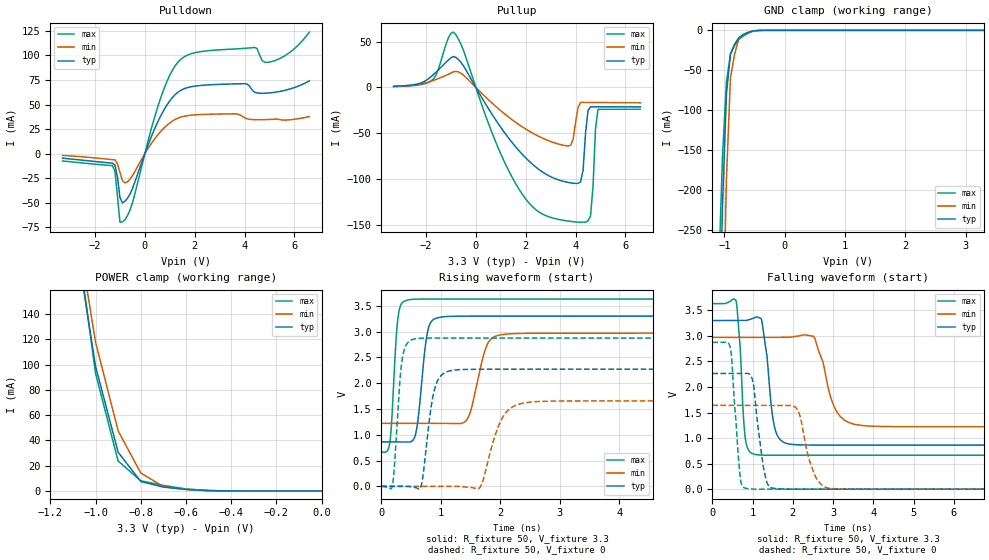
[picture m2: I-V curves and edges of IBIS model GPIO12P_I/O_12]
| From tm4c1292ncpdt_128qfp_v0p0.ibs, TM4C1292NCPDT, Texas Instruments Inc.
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|   Model Cell GPIO12P_I/O_12
[Model]   GPIO12P_I/O_12
Model_type   I/O
Polarity   Non-Inverting
Enable   Active-Low
Vinl =  0.8
Vinh =  2
Cref =  15.0000pF
Rref =  100.0000M
Vref =  0V
Vmeas =  1.65
C_comp   6.029616p   5.226915p   6.778838p
[Model Spec]
Vinl   0.8   0.8   0.8
Vinh   2   2   2
[Temperature Range]   25   125   -40
[Voltage Range]   3.3   2.97   3.63
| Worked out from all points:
|   slope of the pulldown table from 0 to 0.495 V, typ, clamps not added: 15.9 ohm
|   slope of the pullup table from 0 to 0.495 V, typ, clamps not added: 21.8 ohm
|   GND clamp passes 1 mA (typ) near -0.53 V on its own axis
|   POWER clamp passes 1 mA (typ) near -0.58 V on its own axis
|   rising waveform, R_fixture 50, V_fixture 3.3: 20-80 % time 127ps typ, 210ps min, 85.9ps max; typ from 0.861 V to 3.3 V
|   rising waveform, R_fixture 50, V_fixture 0: 20-80 % time 153ps typ, 270ps min, 102ps max; typ from 0 V to 2.26 V
|   falling waveform, R_fixture 50, V_fixture 3.3: 20-80 % time 195ps typ, 372ps min, 122ps max; typ from 3.3 V to 0.861 V
|   falling waveform, R_fixture 50, V_fixture 0: 20-80 % time 208ps typ, 306ps min, 151ps max; typ from 2.26 V to 0 V
| Nom Voltages:
|   IBIASFET=3.3, VDDC=1.2, VDD=3.3, GND=0
| Min Voltages:
|   IBIASFET=2.97, VDDC=1.08, VDD=2.97, GND=0
| Max Voltages:
|   IBIASFET=3.63, VDDC=1.32, VDD=3.63, GND=0
[POWER_clamp]
|   voltage   I(typ)   I(min)   I(max)
-3.3V     3.668A     4.187A     4.057A
-1.067V   175.6mA    191.7mA    181.3mA
-1.033V   137.2mA    154.7mA    137.2mA
-1V       98.66mA    117.8mA    93.17mA
-900mV    30.66mA    47.6mA     23.68mA
-800mV    7.454mA    14.17mA    8.045mA
-700mV    3.021mA    3.466mA    4.326mA
-600mV    1.166mA    1.15mA     1.613mA
-500mV    219.7uA    295.1uA    245.5uA
0V        69.07pA    1.982nA    9.028pA
[Pulldown]
|   voltage   I(typ)   I(min)   I(max)
-3.3V     -4.531mA   -1.809mA   -7.41mA
-1.3V     -9.628mA   -6.013mA   -12.13mA
-1.2V     -11.53mA   -6.246mA   -17.7mA
-1V       -44.52mA   -18.9mA    -69.71mA
-900mV    -49.91mA   -27.35mA   -69.41mA
-500mV    -35.64mA   -22.45mA   -50.16mA
700mV     41.51mA    24.42mA    61.45mA
1.4V      63.88mA    36.91mA    95.09mA
4V        71.26mA    36.57mA    107.3mA
4.4V      62.7mA     34.65mA    108.2mA
5V        61.9mA     34.87mA    93.27mA
6.6V      74.13mA    37.78mA    123.8mA
[Pullup]
|   voltage   I(typ)   I(min)   I(max)
-3.3V     1.279mA    1.197mA    982.3uA
-1.7V     14.18mA    7.771mA    9.423mA
-900mV    33.79mA    17.11mA    60.55mA
1.8V      -71.23mA   -41.94mA   -114.2mA
3.7V      -103.8mA   -63.94mA   -146mA
4V        -104.9mA   -38.28mA   -147mA
4.3V      -90.74mA   -16.33mA   -147.2mA
4.5V      -25.16mA   -16.35mA   -145.8mA
4.6V      -21.1mA    -16.37mA   -140.6mA
4.8V      -21.09mA   -16.4mA    -44.84mA
4.9V      -21.08mA   -16.42mA   -23.95mA
6.6V      -21.2mA    -16.74mA   -23.82mA
[GND_clamp]
|   voltage   I(typ)   I(min)   I(max)
-3.3V     -18.01A    -17.27A    -18.6A
-1.1V     -459.9mA   -734.3mA   -318.7mA
-1.033V   -223.6mA   -411.6mA   -160.4mA
-966.7mV  -80.12mA   -186.8mA   -64.21mA
-900mV    -29.51mA   -59.8mA    -30.11mA
-833.3mV  -17.66mA   -30.4mA    -19.41mA
-766.7mV  -9.785mA   -12.28mA   -11.96mA
-700mV    -5.884mA   -5.445mA   -7.749mA
-500mV    -484.3uA   -573uA     -552.3uA
-366.7mV  -23.48uA   -48.41uA   -21.82uA
3.3V      69.07pA    6.412uA    7.794pA
[Ramp]
| variable   typ   min   max
dV/dt_f  1.5054176/0.20241459n  1.0791279/0.38581502n  1.8336291/0.12747084n
dV/dt_r  1.3955443/0.15677185n  1.0245114/0.27733281n  1.7538476/0.10287361n
R_load = 50
[Rising Waveform]
R_fixture = 50
V_fixture = 3.3
V_fixture_min = 2.97
V_fixture_max = 3.63
|   time   V(typ)   V(min)   V(max)
0s        861.5mV    1.221V     663.5mV
153.3ps   861.5mV    1.221V     944.6mV
290.5ps   861.5mV    1.221V     3.351V
479.8ps   859.5mV    1.221V     3.62V
605.7ps   1.192V     1.221V     3.629V
789.1ps   3.053V     1.221V     3.63V
1.031ns   3.285V     1.221V     3.63V
1.447ns   3.299V     1.308V     3.63V
2.154ns   3.3V       2.956V     3.63V
20.01ns   3.3V       2.97V      3.63V
[Rising Waveform]
R_fixture = 50
V_fixture = 0
V_fixture_min = 0
V_fixture_max = 0
|   time   V(typ)   V(min)   V(max)
0s        0V         0V         0V
181.3ps   0V         0V         -13.98mV
350.9ps   0V         0V         2.466V
592.4ps   -31.5mV    0V         2.864V
918.8ps   1.974V     0V         2.874V
1.215ns   2.252V     0V         2.874V
1.657ns   2.269V     -24.92mV   2.874V
2.033ns   2.27V      1.326V     2.874V
2.584ns   2.271V     1.641V     2.874V
20.02ns   2.264V     1.646V     2.872V
[Falling Waveform]
R_fixture = 50
V_fixture = 3.3
V_fixture_min = 2.97
V_fixture_max = 3.63
|   time   V(typ)   V(min)   V(max)
0s        3.3V       2.97V      3.63V
587.7ps   3.3V       2.97V      3.691V
815ps     3.3V       2.97V      1.016V
1.069ns   3.365V     2.97V      677.8mV
1.238ns   3.251V     2.97V      666.2mV
1.543ns   1.221V     2.97V      664.1mV
1.916ns   882.4mV    2.972V     664.1mV
2.519ns   862.5mV    2.986V     664.2mV
3.673ns   861.6mV    1.251V     664.2mV
20.01ns   861.5mV    1.221V     664.2mV
[Falling Waveform]
R_fixture = 50
V_fixture = 0
V_fixture_min = 0
V_fixture_max = 0
|   time   V(typ)   V(min)   V(max)
0s        2.263V     1.64V      2.872V
445.8ps   2.263V     1.64V      2.767V
689.9ps   2.263V     1.64V      249.9mV
853.6ps   2.266V     1.64V      12.44mV
1.017ns   2.071V     1.64V      0V
1.323ns   230.5mV    1.64V      0V
1.543ns   14.29mV    1.64V      0V
2.114ns   0V         1.554V     0V
2.951ns   0V         14.14mV    0V
20.02ns   0V         0V         0V
